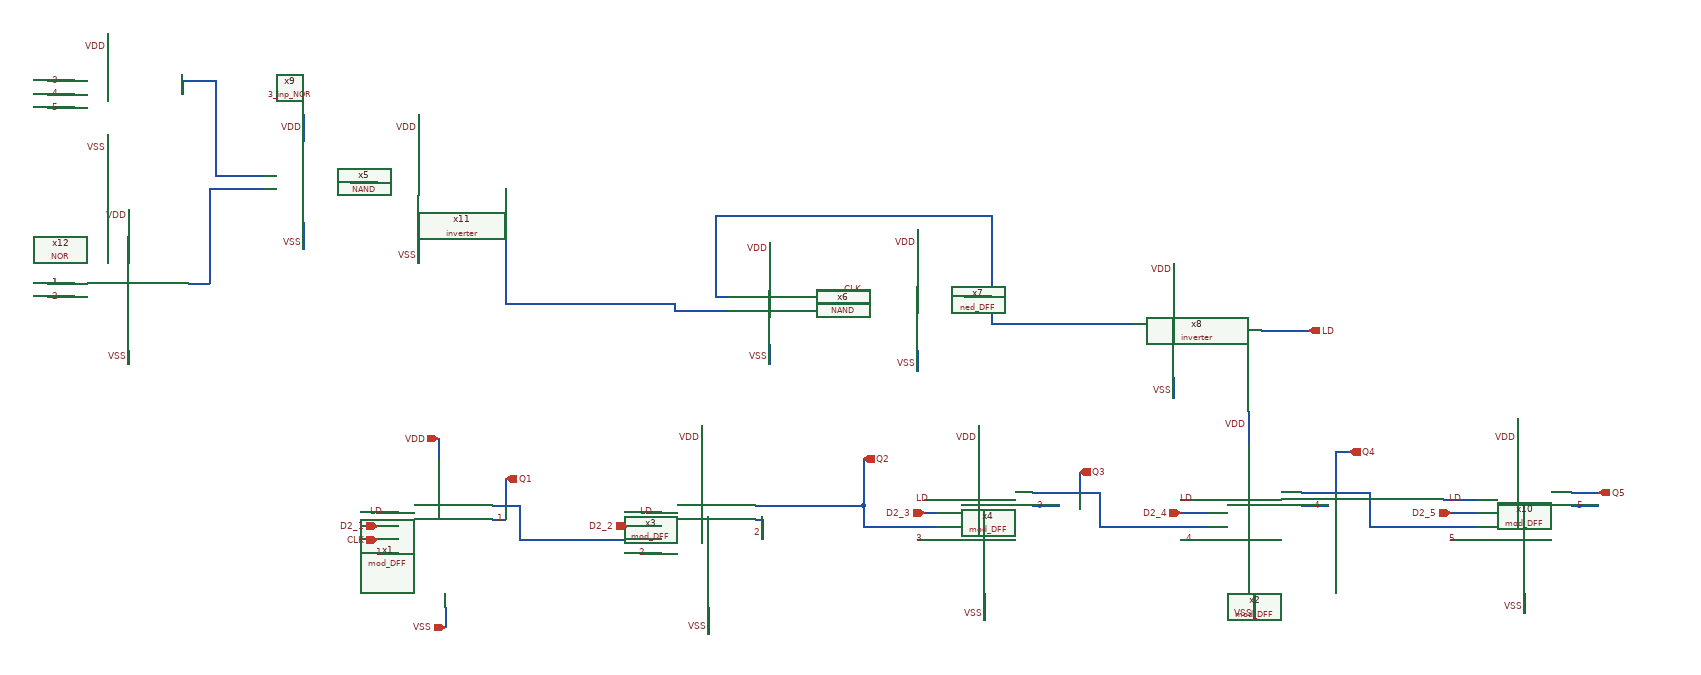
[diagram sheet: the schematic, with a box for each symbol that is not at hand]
v {xschem version=3.1.0 file_version=1.2
}
G {}
K {}
V {}
S {}
E {}
N -280 -100 -260 -100 {
lab=1}
N -450 -50 -420 -50 {
lab=1}
N -450 -90 -420 -90 {
lab=D2_1}
N -450 -70 -420 -70 {
lab=CLK}
N -360 -220 -360 -190 {
lab=VDD}
N -350 30 -350 60 {
lab=VSS}
N -280 -120 -250 -120 {
lab=Q1}
N -250 -120 -240 -120 {
lab=Q1}
N -240 -120 -240 -80 {
lab=Q1}
N -70 -70 -30 -70 {
lab=Q1}
N 860 -380 900 -380 {
lab=LD}
N -450 -110 -420 -110 {
lab=LD}
N -50 -110 -30 -110 {
lab=LD}
N -940 -450 -900 -450 {
lab=1}
N -940 -430 -900 -430 {
lab=2}
N -940 -750 -900 -750 {
lab=3}
N -820 -560 -820 -530 {
lab=VDD}
N -820 -350 -820 -330 {
lab=VSS}
N -10 -410 70 -410 {
lab=#net1}
N 460 -550 460 -390 {
lab=#net2}
N 50 -550 460 -550 {
lab=#net2}
N 50 -550 50 -430 {
lab=#net2}
N 50 -430 70 -430 {
lab=#net2}
N 460 -390 520 -390 {
lab=#net2}
N 350 -530 350 -500 {
lab=VDD}
N 130 -510 130 -480 {
lab=VDD}
N 130 -360 130 -330 {
lab=VSS}
N 350 -350 350 -320 {
lab=VSS}
N 730 -480 730 -450 {
lab=VDD}
N 30 -240 30 -190 {
lab=VDD}
N 340 -90 380 -90 {
lab=Q2}
N 520 -120 560 -120 {
lab=3}
N 110 -100 120 -100 {
lab=2}
N 120 -100 120 -70 {
lab=2}
N 360 -110 380 -110 {
lab=D2_3}
N -50 -90 -30 -90 {
lab=D2_2}
N -260 -160 -260 -120 {
lab=Q1}
N 270 -190 270 -140 {
lab=Q2}
N 520 -140 560 -140 {
lab=Q3}
N -80 -90 -50 -90 {
lab=D2_2}
N 440 -240 440 -210 {
lab=VDD}
N 450 10 450 50 {
lab=VSS}
N -60 -50 -30 -50 {
lab=2}
N 350 -70 380 -70 {
lab=3}
N 250 -440 280 -440 {
lab=CLK}
N 360 -130 380 -130 {
lab=LD}
N 270 -140 270 -130 {
lab=Q2}
N -210 -420 -20 -420 {
lab=#net1}
N -10 -420 -10 -410 {
lab=#net1}
N -20 -420 -10 -420 {
lab=#net1}
N 520 -390 670 -390 {
lab=#net2}
N 900 -380 930 -380 {
lab=LD}
N -240 -80 -240 -70 {
lab=Q1}
N -240 -70 -70 -70 {
lab=Q1}
N 110 -120 270 -120 {
lab=Q2}
N 270 -130 270 -120 {
lab=Q2}
N 270 -120 270 -90 {
lab=Q2}
N 270 -90 340 -90 {
lab=Q2}
N 200 -420 280 -420 {
lab=#net3}
N 730 -310 730 -280 {
lab=VSS}
N 40 30 40 70 {
lab=VSS}
N 420 -430 460 -430 {
lab=#net2}
N 560 -140 620 -140 {
lab=Q3}
N 620 -90 780 -90 {
lab=Q3}
N 620 -140 620 -90 {
lab=Q3}
N 590 -170 590 -140 {
lab=Q3}
N 740 -130 780 -130 {
lab=LD}
N 740 -110 780 -110 {
lab=D2_4}
N 740 -70 780 -70 {
lab=4}
N 840 -260 840 -210 {
lab=VDD}
N 850 10 850 50 {
lab=VSS}
N 920 -120 960 -120 {
lab=4}
N 920 -140 960 -140 {
lab=Q4}
N -850 -820 -850 -790 {
lab=VDD}
N -850 -670 -850 -650 {
lab=VSS}
N -940 -730 -900 -730 {
lab=4}
N -730 -750 -690 -750 {
lab=#net4}
N -690 -750 -690 -610 {
lab=#net4}
N -690 -610 -620 -610 {
lab=#net4}
N -730 -450 -700 -450 {
lab=#net5}
N -700 -590 -700 -450 {
lab=#net5}
N -700 -590 -620 -590 {
lab=#net5}
N -490 -600 -450 -600 {
lab=#net6}
N -560 -700 -560 -660 {
lab=VDD}
N -560 -540 -560 -500 {
lab=VSS}
N -390 -700 -390 -660 {
lab=VDD}
N -390 -520 -390 -480 {
lab=VSS}
N -260 -590 -260 -420 {
lab=#net1}
N -260 -420 -210 -420 {
lab=#net1}
N 960 -140 1020 -140 {
lab=Q4}
N 1020 -140 1020 -90 {
lab=Q4}
N 1020 -90 1180 -90 {
lab=Q4}
N 1130 -130 1180 -130 {
lab=LD}
N 1140 -110 1180 -110 {
lab=D2_5}
N 970 -200 970 -140 {
lab=Q4}
N 970 -200 990 -200 {
lab=Q4}
N 1140 -70 1180 -70 {
lab=5}
N 1320 -140 1360 -140 {
lab=Q5}
N 1320 -120 1360 -120 {
lab=5}
N 1240 -250 1240 -210 {
lab=VDD}
N 1250 10 1250 40 {
lab=VSS}
N -740 -750 -740 -730 {
lab=#net4}
N -740 -750 -730 -750 {
lab=#net4}
N -940 -710 -900 -710 {
lab=4}
C {mod_DFF.sym} -270 -80 0 0 {name=x1}
C {mod_DFF.sym} 120 -80 0 0 {name=x3}
C {mod_DFF.sym} 530 -100 0 0 {name=x4}
C {devices/lab_wire.sym} -440 -110 0 0 {name=p2 sig_type=std_logic lab=LD}
C {devices/lab_wire.sym} -40 -110 0 0 {name=p3 sig_type=std_logic lab=LD}
C {devices/iopin.sym} -360 -220 3 0 {name=p4 lab=VDD}
C {devices/iopin.sym} -350 60 1 0 {name=p5 lab=VSS}
C {devices/lab_wire.sym} -820 -550 0 0 {name=p6 sig_type=std_logic lab=VDD}
C {devices/lab_wire.sym} -820 -340 0 0 {name=p7 sig_type=std_logic lab=VSS}
C {devices/lab_wire.sym} 130 -500 0 0 {name=p8 sig_type=std_logic lab=VDD}
C {devices/lab_wire.sym} 350 -510 0 0 {name=p9 sig_type=std_logic lab=VDD}
C {devices/lab_wire.sym} 730 -470 0 0 {name=p10 sig_type=std_logic lab=VDD}
C {devices/lab_wire.sym} 30 -220 0 0 {name=p11 sig_type=std_logic lab=VDD}
C {devices/lab_wire.sym} 130 -340 0 0 {name=p12 sig_type=std_logic lab=VSS}
C {devices/lab_wire.sym} 350 -330 0 0 {name=p13 sig_type=std_logic lab=VSS}
C {devices/lab_wire.sym} 730 -290 0 0 {name=p14 sig_type=std_logic lab=VSS}
C {devices/lab_wire.sym} 40 60 0 0 {name=p15 sig_type=std_logic lab=VSS}
C {devices/opin.sym} 590 -170 3 0 {name=p16 lab=Q3}
C {devices/opin.sym} -260 -160 3 0 {name=p17 lab=Q1}
C {devices/ipin.sym} -450 -90 0 0 {name=p18 lab=D2_1}
C {devices/ipin.sym} -80 -90 0 0 {name=p19 lab=D2_2}
C {devices/lab_wire.sym} 440 -220 0 0 {name=p22 sig_type=std_logic lab=VDD}
C {devices/lab_wire.sym} 450 40 0 0 {name=p23 sig_type=std_logic lab=VSS}
C {devices/ipin.sym} 360 -110 0 0 {name=p24 lab=D2_3}
C {devices/lab_wire.sym} -920 -450 0 0 {name=p27 sig_type=std_logic lab=1}
C {devices/lab_wire.sym} -920 -430 0 0 {name=p28 sig_type=std_logic lab=2}
C {devices/lab_wire.sym} -920 -450 0 0 {name=p29 sig_type=std_logic lab=1}
C {devices/lab_wire.sym} -920 -750 0 0 {name=p30 sig_type=std_logic lab=3}
C {devices/lab_wire.sym} -260 -100 0 0 {name=p31 sig_type=std_logic lab=1}
C {devices/lab_wire.sym} -440 -50 0 0 {name=p32 sig_type=std_logic lab=1}
C {devices/lab_wire.sym} -50 -50 0 0 {name=p33 sig_type=std_logic lab=2}
C {devices/lab_wire.sym} 120 -80 0 0 {name=p34 sig_type=std_logic lab=2}
C {devices/lab_wire.sym} 540 -120 0 0 {name=p35 sig_type=std_logic lab=3}
C {devices/lab_wire.sym} 360 -70 0 0 {name=p36 sig_type=std_logic lab=3}
C {devices/ipin.sym} -450 -70 0 0 {name=p37 lab=CLK}
C {devices/lab_wire.sym} 270 -440 0 0 {name=p38 sig_type=std_logic lab=CLK}
C {devices/opin.sym} 270 -190 3 0 {name=p39 lab=Q2}
C {devices/lab_wire.sym} 370 -130 0 0 {name=p40 sig_type=std_logic lab=LD}
C {devices/opin.sym} 930 -380 0 0 {name=p41 lab=LD}
C {NAND.sym} 220 -410 0 0 {name=x6}
C {inverter.sym} 820 -370 0 0 {name=x8}
C {ned_DFF.sym} 430 -420 0 0 {name=x7}
C {mod_DFF.sym} 930 -100 0 0 {name=x2}
C {devices/lab_wire.sym} 760 -130 0 0 {name=p1 sig_type=std_logic lab=LD}
C {devices/lab_wire.sym} 760 -70 0 0 {name=p20 sig_type=std_logic lab=4}
C {devices/ipin.sym} 740 -110 0 0 {name=p21 lab=D2_4}
C {devices/lab_wire.sym} 840 -240 0 0 {name=p25 sig_type=std_logic lab=VDD}
C {devices/lab_wire.sym} 850 40 0 0 {name=p26 sig_type=std_logic lab=VSS}
C {devices/lab_wire.sym} 950 -120 0 0 {name=p42 sig_type=std_logic lab=4}
C {devices/opin.sym} 990 -200 0 0 {name=p43 lab=Q4}
C {devices/lab_wire.sym} -850 -650 0 0 {name=p44 sig_type=std_logic lab=VSS}
C {devices/lab_wire.sym} -850 -800 0 0 {name=p45 sig_type=std_logic lab=VDD}
C {devices/lab_wire.sym} -920 -730 0 0 {name=p46 sig_type=std_logic lab=4}
C {NAND.sym} -470 -590 0 0 {name=x5}
C {inverter.sym} -300 -580 0 0 {name=x11}
C {devices/lab_wire.sym} -560 -680 0 0 {name=p47 sig_type=std_logic lab=VDD}
C {devices/lab_wire.sym} -560 -510 0 0 {name=p48 sig_type=std_logic lab=VSS}
C {devices/lab_wire.sym} -390 -680 0 0 {name=p49 sig_type=std_logic lab=VDD}
C {devices/lab_wire.sym} -390 -490 0 0 {name=p50 sig_type=std_logic lab=VSS}
C {mod_DFF.sym} 1330 -100 0 0 {name=x10}
C {devices/ipin.sym} 1140 -110 0 0 {name=p51 lab=D2_5}
C {devices/opin.sym} 1360 -140 0 0 {name=p52 lab=Q5}
C {devices/lab_wire.sym} 1150 -70 0 0 {name=p53 sig_type=std_logic lab=5}
C {devices/lab_wire.sym} 1340 -120 0 0 {name=p54 sig_type=std_logic lab=5}
C {devices/lab_wire.sym} 1160 -130 0 0 {name=p55 sig_type=std_logic lab=LD}
C {devices/lab_wire.sym} 1240 -220 0 0 {name=p56 sig_type=std_logic lab=VDD}
C {devices/lab_wire.sym} 1250 30 0 0 {name=p57 sig_type=std_logic lab=VSS}
C {NOR.sym} -750 -430 0 0 {name=x12}
C {3_inp_NOR.sym} -530 -630 0 0 {name=x9}
C {devices/lab_wire.sym} -920 -710 0 0 {name=p58 sig_type=std_logic lab=5}
